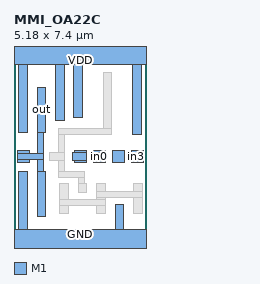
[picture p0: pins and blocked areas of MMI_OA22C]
MACRO MMI_OA22C
	CLASS CORE ;
	FOREIGN MMI_OA22C 0 0 ;
	SIZE 5.18 BY 7.4 ;
	SYMMETRY X Y ;
	SITE CORE1 ;
	PIN out
		DIRECTION output ;
		USE SIGNAL ;
		PORT
			LAYER M1 ;
			RECT 0.9 4.27 1.24 6.03 ;
			LAYER M1 ;
			RECT 0.145 3.445 0.595 3.555 ;
			LAYER M1 ;
			RECT 0.9 3.445 1.13 4.27 ;
			LAYER M1 ;
			RECT 0.145 3.215 1.13 3.445 ;
			LAYER M1 ;
			RECT 0.145 3.105 0.595 3.215 ;
			LAYER M1 ;
			RECT 0.9 2.745 1.13 3.215 ;
			LAYER M1 ;
			RECT 0.9 0.985 1.24 2.745 ;
		END
		AntennaDiffArea 1.8768 ;
	END out
	PIN in1
		DIRECTION input ;
		USE SIGNAL ;
		PORT
			LAYER M1 ;
			RECT 2.365 3.5 2.815 3.555 ;
			LAYER M1 ;
			RECT 2.26 3.16 2.815 3.5 ;
			LAYER M1 ;
			RECT 2.365 3.105 2.815 3.16 ;
		END
		AntennaGateArea 0.6696 ;
	END in1
	PIN GND
		DIRECTION inout ;
		USE GROUND ;
		PORT
			LAYER M1 ;
			RECT 0.18 0.5 0.52 2.745 ;
			LAYER M1 ;
			RECT 3.94 0.5 4.28 1.465 ;
			LAYER M1 ;
			RECT 0 -0.5 5.18 0.5 ;
		END
	END GND
	PIN in2
		DIRECTION input ;
		USE SIGNAL ;
		PORT
			LAYER M1 ;
			RECT 3.845 3.105 4.295 3.555 ;
		END
		AntennaGateArea 0.6696 ;
	END in2
	PIN VDD
		DIRECTION inout ;
		USE POWER ;
		PORT
			LAYER M1 ;
			RECT 0 6.9 5.18 7.9 ;
			LAYER M1 ;
			RECT 0.18 4.27 0.52 6.9 ;
			LAYER M1 ;
			RECT 1.62 4.75 1.96 6.9 ;
			LAYER M1 ;
			RECT 2.32 4.855 2.66 6.9 ;
			LAYER M1 ;
			RECT 4.62 4.205 4.96 6.9 ;
		END
	END VDD
	PIN in3
		DIRECTION input ;
		USE SIGNAL ;
		PORT
			LAYER M1 ;
			RECT 4.585 3.105 5.035 3.555 ;
		END
		AntennaGateArea 0.6696 ;
	END in3
	PIN in0
		DIRECTION input ;
		USE SIGNAL ;
		PORT
			LAYER M1 ;
			RECT 3.105 3.5 3.555 3.555 ;
			LAYER M1 ;
			RECT 3.055 3.16 3.555 3.5 ;
			LAYER M1 ;
			RECT 3.105 3.105 3.555 3.16 ;
		END
		AntennaGateArea 0.6696 ;
	END in0
	OBS
		LAYER M1 ;
		RECT 3.47 4.435 3.81 6.605 ;
		LAYER M1 ;
		RECT 1.75 4.205 3.81 4.435 ;
		LAYER M1 ;
		RECT 1.75 3.505 1.98 4.205 ;
		LAYER M1 ;
		RECT 1.38 3.165 1.98 3.505 ;
		LAYER M1 ;
		RECT 1.75 2.755 1.98 3.165 ;
		LAYER M1 ;
		RECT 1.75 2.525 2.73 2.755 ;
		LAYER M1 ;
		RECT 2.5 2.285 2.73 2.525 ;
		LAYER M1 ;
		RECT 1.78 1.64 2.12 2.285 ;
		LAYER M1 ;
		RECT 2.5 1.945 2.84 2.285 ;
		LAYER M1 ;
		RECT 3.22 1.96 3.56 2.285 ;
		LAYER M1 ;
		RECT 4.66 1.96 5 2.285 ;
		LAYER M1 ;
		RECT 3.22 1.73 5 1.96 ;
		LAYER M1 ;
		RECT 3.22 1.64 3.56 1.73 ;
		LAYER M1 ;
		RECT 1.78 1.41 3.56 1.64 ;
		LAYER M1 ;
		RECT 1.78 1.125 2.12 1.41 ;
		LAYER M1 ;
		RECT 3.22 1.125 3.56 1.41 ;
		LAYER M1 ;
		RECT 4.66 1.125 5 1.73 ;
	END
END MMI_OA22C
